VERSION 5.7 ;
BUSBITCHARS "[]" ;
DIVIDERCHAR "/" ;

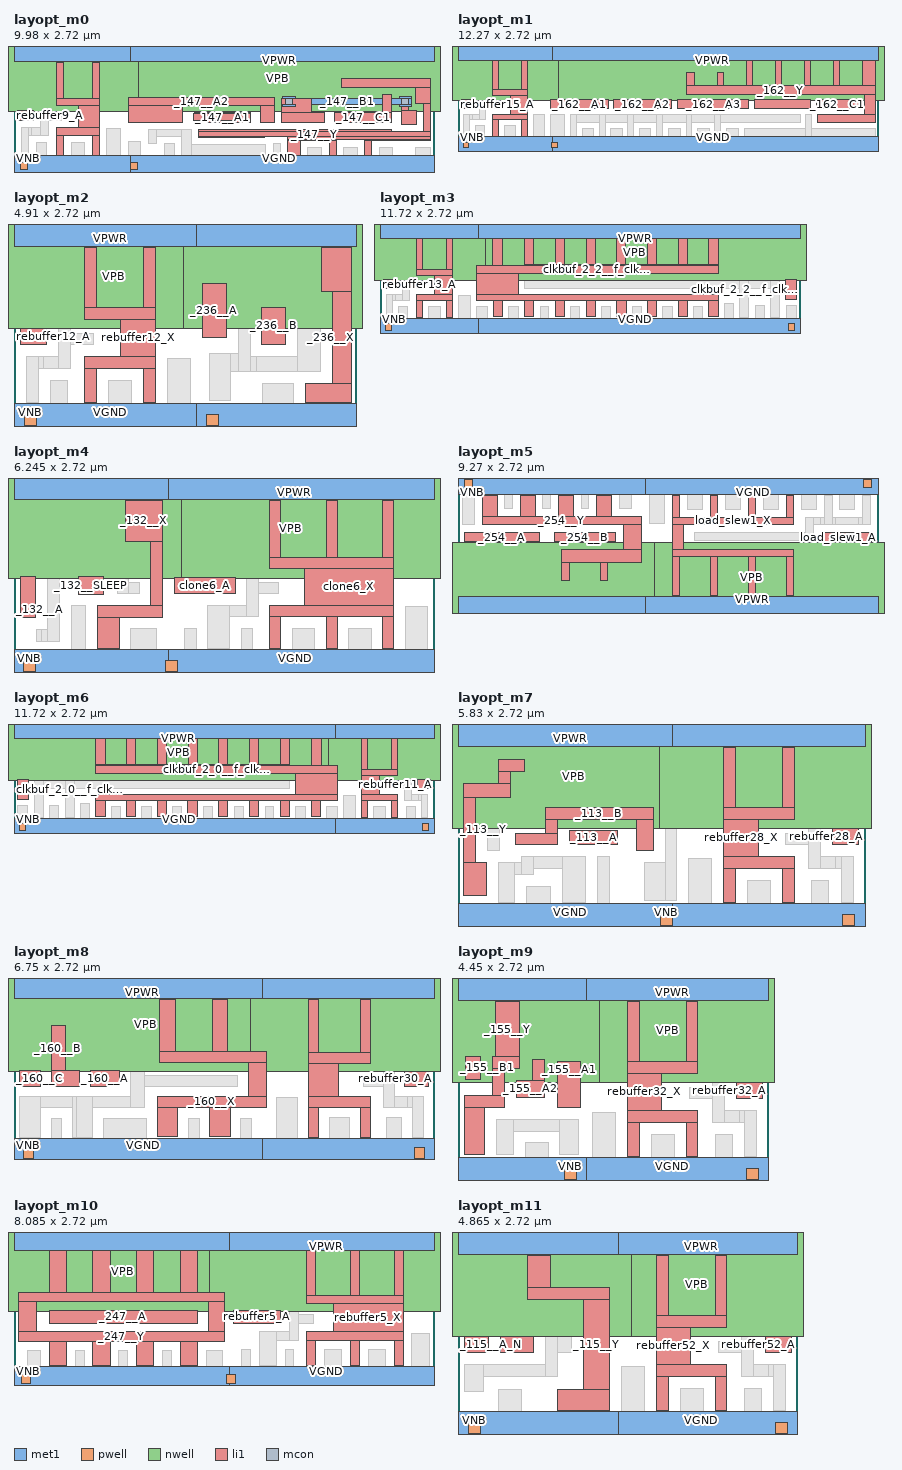
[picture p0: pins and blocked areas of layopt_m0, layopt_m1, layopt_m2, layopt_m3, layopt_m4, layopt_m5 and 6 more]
MACRO layopt_m0
  CLASS BLOCK ;
  FOREIGN layopt_m0 0 0 ;
  ORIGIN 0 0 ;
  SIZE 9.980 BY 2.720 ;
  SYMMETRY X Y ;
  PIN VGND
    DIRECTION INOUT ;
    USE GROUND ;
    SHAPE ABUTMENT ;
    PORT
      LAYER met1 ;
        RECT 0.000 -0.240 2.760 0.240 ;
      LAYER met1 ;
        RECT 2.620 -0.240 9.980 0.240 ;
    END
  END VGND
  PIN VNB
    DIRECTION INOUT ;
    USE GROUND ;
    SHAPE ABUTMENT ;
    PORT
      LAYER pwell ;
        RECT 0.150 -0.085 0.320 0.085 ;
      LAYER pwell ;
        RECT 2.770 -0.085 2.940 0.085 ;
    END
  END VNB
  PIN VPB
    DIRECTION INOUT ;
    USE POWER ;
    SHAPE ABUTMENT ;
    PORT
      LAYER nwell ;
        RECT -0.190 1.305 2.950 2.910 ;
      LAYER nwell ;
        RECT 2.430 1.305 10.170 2.910 ;
    END
  END VPB
  PIN VPWR
    DIRECTION INOUT ;
    USE POWER ;
    SHAPE ABUTMENT ;
    PORT
      LAYER met1 ;
        RECT 0.000 2.480 2.760 2.960 ;
      LAYER met1 ;
        RECT 2.620 2.480 9.980 2.960 ;
    END
  END VPWR
  PIN _147__A1
    DIRECTION INPUT ;
    USE SIGNAL ;
    PORT
      LAYER li1 ;
        RECT 4.275 1.075 5.625 1.245 ;
      LAYER li1 ;
        RECT 4.280 1.035 5.625 1.075 ;
      LAYER li1 ;
        RECT 4.280 1.245 5.625 1.275 ;
    END
  END _147__A1
  PIN _147__A2
    DIRECTION INPUT ;
    USE SIGNAL ;
    PORT
      LAYER li1 ;
        RECT 2.720 1.035 4.005 1.445 ;
      LAYER li1 ;
        RECT 2.720 1.445 6.195 1.625 ;
      LAYER li1 ;
        RECT 5.865 1.035 6.195 1.445 ;
    END
  END _147__A2
  PIN _147__B1
    DIRECTION INPUT ;
    USE SIGNAL ;
    PORT
      LAYER li1 ;
        RECT 6.365 1.035 7.375 1.275 ;
      LAYER li1 ;
        RECT 6.365 1.275 7.080 1.615 ;
      LAYER mcon ;
        RECT 6.450 1.445 6.620 1.615 ;
      LAYER li1 ;
        RECT 9.210 0.995 9.555 1.325 ;
      LAYER li1 ;
        RECT 9.210 1.325 9.380 1.615 ;
      LAYER mcon ;
        RECT 9.210 1.445 9.380 1.615 ;
      LAYER met1 ;
        RECT 6.390 1.415 6.680 1.460 ;
      LAYER met1 ;
        RECT 6.390 1.460 9.440 1.600 ;
      LAYER met1 ;
        RECT 6.390 1.600 6.680 1.645 ;
      LAYER met1 ;
        RECT 9.150 1.415 9.440 1.460 ;
      LAYER met1 ;
        RECT 9.150 1.600 9.440 1.645 ;
    END
  END _147__B1
  PIN _147__C1
    DIRECTION INPUT ;
    USE SIGNAL ;
    PORT
      LAYER li1 ;
        RECT 7.620 1.035 8.970 1.275 ;
      LAYER li1 ;
        RECT 8.750 1.275 8.970 1.695 ;
    END
  END _147__C1
  PIN _147__Y
    DIRECTION OUTPUT ;
    USE SIGNAL ;
    PORT
      LAYER li1 ;
        RECT 4.395 0.675 5.950 0.695 ;
      LAYER li1 ;
        RECT 4.395 0.695 9.895 0.825 ;
      LAYER li1 ;
        RECT 4.395 0.825 8.975 0.865 ;
      LAYER li1 ;
        RECT 6.495 0.255 6.815 0.615 ;
      LAYER li1 ;
        RECT 6.495 0.615 7.665 0.625 ;
      LAYER li1 ;
        RECT 6.495 0.625 9.895 0.695 ;
      LAYER li1 ;
        RECT 7.495 0.255 7.665 0.615 ;
      LAYER li1 ;
        RECT 7.790 1.865 9.895 2.085 ;
      LAYER li1 ;
        RECT 8.335 0.255 8.505 0.615 ;
      LAYER li1 ;
        RECT 8.335 0.615 9.895 0.625 ;
      LAYER li1 ;
        RECT 9.550 1.495 9.895 1.865 ;
      LAYER li1 ;
        RECT 9.725 0.825 9.895 1.495 ;
    END
  END _147__Y
  PIN rebuffer9_A
    DIRECTION INPUT ;
    USE SIGNAL ;
    PORT
      LAYER li1 ;
        RECT 0.090 1.075 0.470 1.315 ;
    END
  END rebuffer9_A
  PIN rebuffer9_X
    DIRECTION OUTPUT ;
    USE SIGNAL ;
    PORT
      LAYER li1 ;
        RECT 1.015 0.255 1.185 0.735 ;
      LAYER li1 ;
        RECT 1.015 0.735 2.025 0.905 ;
      LAYER li1 ;
        RECT 1.015 1.445 2.025 1.615 ;
      LAYER li1 ;
        RECT 1.015 1.615 1.185 2.465 ;
      LAYER li1 ;
        RECT 1.530 0.905 2.025 1.445 ;
      LAYER li1 ;
        RECT 1.855 0.255 2.025 0.735 ;
      LAYER li1 ;
        RECT 1.855 1.615 2.025 2.465 ;
    END
  END rebuffer9_X
  OBS
    LAYER li1 ;
      RECT 2.620 -0.085 2.715 0.085 ;
      RECT 2.715 -0.085 3.015 0.585 ;
      RECT 3.015 -0.085 3.570 0.085 ;
      RECT 3.570 -0.085 3.805 0.525 ;
      RECT 3.805 -0.085 6.155 0.085 ;
      RECT 6.155 -0.085 6.325 0.525 ;
      RECT 6.325 -0.085 6.985 0.085 ;
      RECT 6.985 -0.085 7.315 0.445 ;
      RECT 7.315 -0.085 7.835 0.085 ;
      RECT 7.835 -0.085 8.165 0.445 ;
      RECT 8.165 -0.085 8.675 0.085 ;
      RECT 8.675 -0.085 9.005 0.445 ;
      RECT 9.005 -0.085 9.535 0.085 ;
      RECT 9.535 -0.085 9.890 0.445 ;
      RECT 9.890 -0.085 9.980 0.085 ;
      RECT 2.620 2.635 3.135 2.805 ;
      RECT 3.135 2.255 3.465 2.805 ;
      RECT 3.465 2.635 3.975 2.805 ;
      RECT 3.975 2.275 4.305 2.805 ;
      RECT 4.305 2.635 4.815 2.805 ;
      RECT 4.815 2.275 5.145 2.805 ;
      RECT 5.145 2.635 5.655 2.805 ;
      RECT 5.655 2.275 5.985 2.805 ;
      RECT 5.985 2.635 9.980 2.805 ;
      RECT 6.495 1.785 7.250 2.085 ;
      RECT 7.250 1.445 7.530 2.085 ;
      RECT 7.530 1.445 8.580 1.695 ;
      RECT 2.715 1.795 2.965 2.465 ;
      RECT 2.965 1.795 3.635 2.085 ;
      RECT 3.635 1.795 3.805 2.465 ;
      RECT 3.805 1.795 4.475 2.105 ;
      RECT 4.475 1.795 4.645 2.465 ;
      RECT 4.645 1.795 5.315 2.105 ;
      RECT 5.315 1.795 5.485 2.465 ;
      RECT 5.485 1.795 6.155 2.105 ;
      RECT 6.155 1.795 6.325 2.465 ;
      RECT 6.325 2.255 9.890 2.465 ;
      RECT 3.185 0.530 3.395 0.865 ;
      RECT 3.395 0.695 3.975 0.865 ;
      RECT 3.975 0.255 4.225 0.865 ;
      RECT 4.225 0.255 5.985 0.505 ;
      RECT 0.095 1.485 0.175 2.465 ;
      RECT 0.175 0.255 0.345 0.905 ;
      RECT 0.175 1.485 0.345 2.465 ;
      RECT 0.345 0.735 0.425 0.905 ;
      RECT 0.345 1.485 0.425 2.465 ;
      RECT 0.425 0.735 0.640 0.905 ;
      RECT 0.425 1.485 0.640 1.655 ;
      RECT 0.640 0.735 0.810 1.655 ;
      RECT 0.810 1.075 1.140 1.245 ;
      RECT 0.000 2.635 0.595 2.805 ;
      RECT 0.595 1.835 0.835 2.805 ;
      RECT 0.835 2.635 1.355 2.805 ;
      RECT 1.355 1.835 1.685 2.805 ;
      RECT 1.685 2.635 2.195 2.805 ;
      RECT 2.195 1.485 2.525 2.805 ;
      RECT 2.525 2.635 2.760 2.805 ;
      RECT 0.000 -0.085 0.525 0.085 ;
      RECT 0.525 -0.085 0.765 0.565 ;
      RECT 0.765 -0.085 1.355 0.085 ;
      RECT 1.355 -0.085 1.685 0.565 ;
      RECT 1.685 -0.085 2.195 0.085 ;
      RECT 2.195 -0.085 2.525 0.885 ;
      RECT 2.525 -0.085 2.760 0.085 ;
  END
END layopt_m0

MACRO layopt_m1
  CLASS BLOCK ;
  FOREIGN layopt_m1 0 0 ;
  ORIGIN 0 0 ;
  SIZE 12.270 BY 2.720 ;
  SYMMETRY X Y ;
  PIN VGND
    DIRECTION INOUT ;
    USE GROUND ;
    SHAPE ABUTMENT ;
    PORT
      LAYER met1 ;
        RECT 0.000 -0.240 2.760 0.240 ;
      LAYER met1 ;
        RECT 2.610 -0.240 12.270 0.240 ;
    END
  END VGND
  PIN VNB
    DIRECTION INOUT ;
    USE GROUND ;
    SHAPE ABUTMENT ;
    PORT
      LAYER pwell ;
        RECT 0.150 -0.085 0.320 0.085 ;
      LAYER pwell ;
        RECT 2.735 -0.085 2.905 0.085 ;
    END
  END VNB
  PIN VPB
    DIRECTION INOUT ;
    USE POWER ;
    SHAPE ABUTMENT ;
    PORT
      LAYER nwell ;
        RECT -0.190 1.305 2.950 2.910 ;
      LAYER nwell ;
        RECT 2.420 1.305 12.460 2.910 ;
    END
  END VPB
  PIN VPWR
    DIRECTION INOUT ;
    USE POWER ;
    SHAPE ABUTMENT ;
    PORT
      LAYER met1 ;
        RECT 0.000 2.480 2.760 2.960 ;
      LAYER met1 ;
        RECT 2.610 2.480 12.270 2.960 ;
    END
  END VPWR
  PIN _162__A1
    DIRECTION INPUT ;
    USE SIGNAL ;
    PORT
      LAYER li1 ;
        RECT 2.695 1.055 4.385 1.315 ;
    END
  END _162__A1
  PIN _162__A2
    DIRECTION INPUT ;
    USE SIGNAL ;
    PORT
      LAYER li1 ;
        RECT 4.555 1.055 6.225 1.315 ;
    END
  END _162__A2
  PIN _162__A3
    DIRECTION INPUT ;
    USE SIGNAL ;
    PORT
      LAYER li1 ;
        RECT 6.415 1.055 8.495 1.315 ;
    END
  END _162__A3
  PIN _162__B1
    DIRECTION INPUT ;
    USE SIGNAL ;
    PORT
      LAYER li1 ;
        RECT 8.665 1.055 10.305 1.315 ;
    END
  END _162__B1
  PIN _162__C1
    DIRECTION INPUT ;
    USE SIGNAL ;
    PORT
      LAYER li1 ;
        RECT 10.475 1.055 11.700 1.315 ;
    END
  END _162__C1
  PIN _162__Y
    DIRECTION OUTPUT ;
    USE SIGNAL ;
    PORT
      LAYER li1 ;
        RECT 6.665 1.485 12.185 1.725 ;
      LAYER li1 ;
        RECT 6.665 1.725 6.915 2.115 ;
      LAYER li1 ;
        RECT 7.585 1.725 7.755 2.115 ;
      LAYER li1 ;
        RECT 8.425 1.725 8.615 2.465 ;
      LAYER li1 ;
        RECT 9.285 1.725 9.455 2.465 ;
      LAYER li1 ;
        RECT 10.125 1.725 10.295 2.465 ;
      LAYER li1 ;
        RECT 10.505 0.655 12.185 0.885 ;
      LAYER li1 ;
        RECT 10.965 1.725 11.135 2.465 ;
      LAYER li1 ;
        RECT 11.805 1.725 12.185 2.465 ;
      LAYER li1 ;
        RECT 11.870 0.885 12.185 1.485 ;
    END
  END _162__Y
  PIN rebuffer15_A
    DIRECTION INPUT ;
    USE SIGNAL ;
    PORT
      LAYER li1 ;
        RECT 0.090 1.075 0.470 1.315 ;
    END
  END rebuffer15_A
  PIN rebuffer15_X
    DIRECTION OUTPUT ;
    USE SIGNAL ;
    PORT
      LAYER li1 ;
        RECT 1.015 0.255 1.185 0.735 ;
      LAYER li1 ;
        RECT 1.015 0.735 2.025 0.905 ;
      LAYER li1 ;
        RECT 1.015 1.445 2.025 1.615 ;
      LAYER li1 ;
        RECT 1.015 1.615 1.185 2.465 ;
      LAYER li1 ;
        RECT 1.530 0.905 2.025 1.445 ;
      LAYER li1 ;
        RECT 1.855 0.255 2.025 0.735 ;
      LAYER li1 ;
        RECT 1.855 1.615 2.025 2.465 ;
    END
  END rebuffer15_X
  OBS
    LAYER li1 ;
      RECT 2.610 -0.085 2.695 0.085 ;
      RECT 2.695 -0.085 3.115 0.885 ;
      RECT 3.115 -0.085 3.625 0.085 ;
      RECT 3.625 -0.085 3.955 0.485 ;
      RECT 3.955 -0.085 4.465 0.085 ;
      RECT 4.465 -0.085 4.795 0.485 ;
      RECT 4.795 -0.085 5.305 0.085 ;
      RECT 5.305 -0.085 5.635 0.485 ;
      RECT 5.635 -0.085 6.145 0.085 ;
      RECT 6.145 -0.085 6.495 0.485 ;
      RECT 6.495 -0.085 7.005 0.085 ;
      RECT 7.005 -0.085 7.335 0.485 ;
      RECT 7.335 -0.085 7.845 0.085 ;
      RECT 7.845 -0.085 8.195 0.485 ;
      RECT 8.195 -0.085 12.270 0.085 ;
      RECT 8.365 0.255 10.165 0.485 ;
      RECT 10.165 0.255 10.335 0.885 ;
      RECT 10.335 0.255 12.185 0.485 ;
      RECT 2.695 1.485 3.015 2.465 ;
      RECT 3.015 1.485 3.705 1.725 ;
      RECT 3.705 1.485 3.875 2.465 ;
      RECT 3.875 1.485 4.545 1.725 ;
      RECT 4.545 1.485 4.715 2.465 ;
      RECT 4.715 1.485 5.385 1.725 ;
      RECT 5.385 1.485 5.555 2.115 ;
      RECT 5.555 1.485 6.225 1.725 ;
      RECT 6.225 1.485 6.475 2.115 ;
      RECT 3.285 0.255 3.455 0.885 ;
      RECT 3.455 0.655 4.125 0.885 ;
      RECT 4.125 0.255 4.295 0.885 ;
      RECT 4.295 0.655 4.965 0.885 ;
      RECT 4.965 0.255 5.135 0.885 ;
      RECT 5.135 0.655 5.805 0.885 ;
      RECT 5.805 0.255 5.975 0.885 ;
      RECT 5.975 0.655 6.665 0.885 ;
      RECT 6.665 0.255 6.835 0.885 ;
      RECT 6.835 0.655 7.505 0.885 ;
      RECT 7.505 0.255 7.675 0.885 ;
      RECT 7.675 0.655 9.995 0.885 ;
      RECT 2.610 2.635 3.205 2.805 ;
      RECT 3.205 1.895 3.535 2.805 ;
      RECT 3.535 2.635 4.045 2.805 ;
      RECT 4.045 1.895 4.375 2.805 ;
      RECT 4.375 2.635 8.785 2.805 ;
      RECT 8.785 1.895 9.115 2.805 ;
      RECT 9.115 2.635 9.625 2.805 ;
      RECT 9.625 1.895 9.955 2.805 ;
      RECT 9.955 2.635 10.465 2.805 ;
      RECT 10.465 1.895 10.795 2.805 ;
      RECT 10.795 2.635 11.305 2.805 ;
      RECT 11.305 1.895 11.635 2.805 ;
      RECT 11.635 2.635 12.270 2.805 ;
      RECT 4.885 1.895 5.215 2.465 ;
      RECT 5.215 2.295 5.725 2.465 ;
      RECT 5.725 1.895 6.055 2.465 ;
      RECT 6.055 2.295 7.085 2.465 ;
      RECT 7.085 1.895 7.415 2.465 ;
      RECT 7.415 2.295 7.925 2.465 ;
      RECT 7.925 1.895 8.255 2.465 ;
      RECT 0.095 1.485 0.175 2.465 ;
      RECT 0.175 0.255 0.345 0.905 ;
      RECT 0.175 1.485 0.345 2.465 ;
      RECT 0.345 0.735 0.425 0.905 ;
      RECT 0.345 1.485 0.425 2.465 ;
      RECT 0.425 0.735 0.640 0.905 ;
      RECT 0.425 1.485 0.640 1.655 ;
      RECT 0.640 0.735 0.810 1.655 ;
      RECT 0.810 1.075 1.140 1.245 ;
      RECT 0.000 2.635 0.595 2.805 ;
      RECT 0.595 1.835 0.835 2.805 ;
      RECT 0.835 2.635 1.355 2.805 ;
      RECT 1.355 1.835 1.685 2.805 ;
      RECT 1.685 2.635 2.195 2.805 ;
      RECT 2.195 1.485 2.525 2.805 ;
      RECT 2.525 2.635 2.760 2.805 ;
      RECT 0.000 -0.085 0.525 0.085 ;
      RECT 0.525 -0.085 0.765 0.565 ;
      RECT 0.765 -0.085 1.355 0.085 ;
      RECT 1.355 -0.085 1.685 0.565 ;
      RECT 1.685 -0.085 2.195 0.085 ;
      RECT 2.195 -0.085 2.525 0.885 ;
      RECT 2.525 -0.085 2.760 0.085 ;
  END
END layopt_m1

MACRO layopt_m2
  CLASS BLOCK ;
  FOREIGN layopt_m2 0 0 ;
  ORIGIN 0 0 ;
  SIZE 4.910 BY 2.720 ;
  SYMMETRY X Y ;
  PIN VGND
    DIRECTION INOUT ;
    USE GROUND ;
    SHAPE ABUTMENT ;
    PORT
      LAYER met1 ;
        RECT 0.000 -0.240 2.760 0.240 ;
      LAYER met1 ;
        RECT 2.610 -0.240 4.910 0.240 ;
    END
  END VGND
  PIN VNB
    DIRECTION INOUT ;
    USE GROUND ;
    SHAPE ABUTMENT ;
    PORT
      LAYER pwell ;
        RECT 0.150 -0.085 0.320 0.085 ;
      LAYER pwell ;
        RECT 2.755 -0.085 2.925 0.085 ;
    END
  END VNB
  PIN VPB
    DIRECTION INOUT ;
    USE POWER ;
    SHAPE ABUTMENT ;
    PORT
      LAYER nwell ;
        RECT -0.190 1.305 2.950 2.910 ;
      LAYER nwell ;
        RECT 2.420 1.305 5.100 2.910 ;
    END
  END VPB
  PIN VPWR
    DIRECTION INOUT ;
    USE POWER ;
    SHAPE ABUTMENT ;
    PORT
      LAYER met1 ;
        RECT 0.000 2.480 2.760 2.960 ;
      LAYER met1 ;
        RECT 2.610 2.480 4.910 2.960 ;
    END
  END VPWR
  PIN _236__A
    DIRECTION INPUT ;
    USE SIGNAL ;
    PORT
      LAYER li1 ;
        RECT 2.695 1.185 3.040 1.955 ;
    END
  END _236__A
  PIN _236__B
    DIRECTION INPUT ;
    USE SIGNAL ;
    PORT
      LAYER li1 ;
        RECT 3.550 1.080 3.880 1.615 ;
    END
  END _236__B
  PIN _236__X
    DIRECTION OUTPUT ;
    USE SIGNAL ;
    PORT
      LAYER li1 ;
        RECT 4.170 0.255 4.825 0.525 ;
      LAYER li1 ;
        RECT 4.400 1.835 4.825 2.465 ;
      LAYER li1 ;
        RECT 4.560 0.525 4.825 1.835 ;
    END
  END _236__X
  PIN rebuffer12_A
    DIRECTION INPUT ;
    USE SIGNAL ;
    PORT
      LAYER li1 ;
        RECT 0.090 1.075 0.470 1.315 ;
    END
  END rebuffer12_A
  PIN rebuffer12_X
    DIRECTION OUTPUT ;
    USE SIGNAL ;
    PORT
      LAYER li1 ;
        RECT 1.015 0.255 1.185 0.735 ;
      LAYER li1 ;
        RECT 1.015 0.735 2.025 0.905 ;
      LAYER li1 ;
        RECT 1.015 1.445 2.025 1.615 ;
      LAYER li1 ;
        RECT 1.015 1.615 1.185 2.465 ;
      LAYER li1 ;
        RECT 1.530 0.905 2.025 1.445 ;
      LAYER li1 ;
        RECT 1.855 0.255 2.025 0.735 ;
      LAYER li1 ;
        RECT 1.855 1.615 2.025 2.465 ;
    END
  END rebuffer12_X
  OBS
    LAYER li1 ;
      RECT 2.610 -0.085 3.560 0.085 ;
      RECT 3.560 -0.085 4.000 0.525 ;
      RECT 4.000 -0.085 4.910 0.085 ;
      RECT 2.610 2.635 2.770 2.805 ;
      RECT 2.770 2.175 3.040 2.805 ;
      RECT 3.040 2.635 3.720 2.805 ;
      RECT 3.720 1.835 4.230 2.805 ;
      RECT 4.230 2.635 4.910 2.805 ;
      RECT 2.795 0.280 3.100 0.950 ;
      RECT 3.100 0.695 3.210 0.950 ;
      RECT 3.210 0.695 3.380 2.465 ;
      RECT 3.380 0.695 3.475 0.910 ;
      RECT 3.380 2.135 3.475 2.465 ;
      RECT 3.475 0.695 4.060 0.910 ;
      RECT 4.060 0.695 4.390 1.435 ;
      RECT 0.095 1.485 0.175 2.465 ;
      RECT 0.175 0.255 0.345 0.905 ;
      RECT 0.175 1.485 0.345 2.465 ;
      RECT 0.345 0.735 0.425 0.905 ;
      RECT 0.345 1.485 0.425 2.465 ;
      RECT 0.425 0.735 0.640 0.905 ;
      RECT 0.425 1.485 0.640 1.655 ;
      RECT 0.640 0.735 0.810 1.655 ;
      RECT 0.810 1.075 1.140 1.245 ;
      RECT 0.000 2.635 0.595 2.805 ;
      RECT 0.595 1.835 0.835 2.805 ;
      RECT 0.835 2.635 1.355 2.805 ;
      RECT 1.355 1.835 1.685 2.805 ;
      RECT 1.685 2.635 2.195 2.805 ;
      RECT 2.195 1.485 2.525 2.805 ;
      RECT 2.525 2.635 2.760 2.805 ;
      RECT 0.000 -0.085 0.525 0.085 ;
      RECT 0.525 -0.085 0.765 0.565 ;
      RECT 0.765 -0.085 1.355 0.085 ;
      RECT 1.355 -0.085 1.685 0.565 ;
      RECT 1.685 -0.085 2.195 0.085 ;
      RECT 2.195 -0.085 2.525 0.885 ;
      RECT 2.525 -0.085 2.760 0.085 ;
  END
END layopt_m2

MACRO layopt_m3
  CLASS BLOCK ;
  FOREIGN layopt_m3 0 0 ;
  ORIGIN 0 0 ;
  SIZE 11.720 BY 2.720 ;
  SYMMETRY X Y ;
  PIN VGND
    DIRECTION INOUT ;
    USE GROUND ;
    SHAPE ABUTMENT ;
    PORT
      LAYER met1 ;
        RECT 0.000 -0.240 2.760 0.240 ;
      LAYER met1 ;
        RECT 2.520 -0.240 11.720 0.240 ;
    END
  END VGND
  PIN VNB
    DIRECTION INOUT ;
    USE GROUND ;
    SHAPE ABUTMENT ;
    PORT
      LAYER pwell ;
        RECT 0.150 -0.085 0.320 0.085 ;
      LAYER pwell ;
        RECT 11.405 -0.085 11.575 0.085 ;
    END
  END VNB
  PIN VPB
    DIRECTION INOUT ;
    USE POWER ;
    SHAPE ABUTMENT ;
    PORT
      LAYER nwell ;
        RECT -0.190 1.305 2.950 2.910 ;
      LAYER nwell ;
        RECT 2.330 1.305 11.910 2.910 ;
    END
  END VPB
  PIN VPWR
    DIRECTION INOUT ;
    USE POWER ;
    SHAPE ABUTMENT ;
    PORT
      LAYER met1 ;
        RECT 0.000 2.480 2.760 2.960 ;
      LAYER met1 ;
        RECT 2.520 2.480 11.720 2.960 ;
    END
  END VPWR
  PIN clkbuf_2_2__f_clk_A
    DIRECTION INPUT ;
    USE SIGNAL ;
    PORT
      LAYER li1 ;
        RECT 11.320 0.765 11.635 1.325 ;
    END
  END clkbuf_2_2__f_clk_A
  PIN clkbuf_2_2__f_clk_X
    DIRECTION OUTPUT ;
    USE SIGNAL ;
    PORT
      LAYER li1 ;
        RECT 9.180 0.280 9.440 0.735 ;
      LAYER li1 ;
        RECT 2.695 0.735 9.440 0.905 ;
      LAYER li1 ;
        RECT 2.695 1.495 9.440 1.720 ;
      LAYER li1 ;
        RECT 4.035 1.720 9.440 1.735 ;
      LAYER li1 ;
        RECT 9.180 1.735 9.440 2.460 ;
      LAYER li1 ;
        RECT 8.320 0.280 8.580 0.735 ;
      LAYER li1 ;
        RECT 8.320 1.735 8.580 2.460 ;
      LAYER li1 ;
        RECT 7.460 0.280 7.720 0.735 ;
      LAYER li1 ;
        RECT 7.460 1.735 7.720 2.460 ;
      LAYER li1 ;
        RECT 6.600 0.280 6.875 0.735 ;
      LAYER li1 ;
        RECT 6.600 1.735 6.860 2.460 ;
      LAYER li1 ;
        RECT 5.755 0.280 6.015 0.735 ;
      LAYER li1 ;
        RECT 5.755 1.735 6.015 2.460 ;
      LAYER li1 ;
        RECT 4.895 0.280 5.155 0.735 ;
      LAYER li1 ;
        RECT 4.895 1.735 5.155 2.460 ;
      LAYER li1 ;
        RECT 4.035 0.280 4.295 0.735 ;
      LAYER li1 ;
        RECT 4.035 1.735 4.295 2.460 ;
      LAYER li1 ;
        RECT 2.695 0.905 3.860 1.495 ;
      LAYER li1 ;
        RECT 3.165 0.280 3.425 0.735 ;
      LAYER li1 ;
        RECT 3.135 1.720 3.425 2.460 ;
    END
  END clkbuf_2_2__f_clk_X
  PIN rebuffer13_A
    DIRECTION INPUT ;
    USE SIGNAL ;
    PORT
      LAYER li1 ;
        RECT 0.090 1.075 0.470 1.315 ;
    END
  END rebuffer13_A
  PIN rebuffer13_X
    DIRECTION OUTPUT ;
    USE SIGNAL ;
    PORT
      LAYER li1 ;
        RECT 1.015 0.255 1.185 0.735 ;
      LAYER li1 ;
        RECT 1.015 0.735 2.025 0.905 ;
      LAYER li1 ;
        RECT 1.015 1.445 2.025 1.615 ;
      LAYER li1 ;
        RECT 1.015 1.615 1.185 2.465 ;
      LAYER li1 ;
        RECT 1.530 0.905 2.025 1.445 ;
      LAYER li1 ;
        RECT 1.855 0.255 2.025 0.735 ;
      LAYER li1 ;
        RECT 1.855 1.615 2.025 2.465 ;
    END
  END rebuffer13_X
  OBS
    LAYER li1 ;
      RECT 11.625 2.635 11.720 2.805 ;
      RECT 11.330 1.825 11.625 2.805 ;
      RECT 10.730 2.635 11.330 2.805 ;
      RECT 10.470 1.825 10.730 2.805 ;
      RECT 9.870 2.635 10.470 2.805 ;
      RECT 9.610 1.835 9.870 2.805 ;
      RECT 9.010 2.630 9.610 2.805 ;
      RECT 8.750 1.905 9.010 2.805 ;
      RECT 8.150 2.630 8.750 2.805 ;
      RECT 7.890 1.905 8.150 2.805 ;
      RECT 7.290 2.630 7.890 2.805 ;
      RECT 7.030 1.905 7.290 2.805 ;
      RECT 6.430 2.630 7.030 2.805 ;
      RECT 6.185 1.905 6.430 2.805 ;
      RECT 5.570 2.630 6.185 2.805 ;
      RECT 5.325 1.905 5.570 2.805 ;
      RECT 4.710 2.630 5.325 2.805 ;
      RECT 4.465 1.905 4.710 2.805 ;
      RECT 3.850 2.630 4.465 2.805 ;
      RECT 3.595 1.905 3.850 2.805 ;
      RECT 2.965 2.635 3.595 2.805 ;
      RECT 2.695 1.890 2.965 2.805 ;
      RECT 2.520 2.635 2.695 2.805 ;
      RECT 11.635 -0.085 11.720 0.085 ;
      RECT 11.330 -0.085 11.635 0.595 ;
      RECT 10.730 -0.085 11.330 0.085 ;
      RECT 10.470 -0.085 10.730 0.610 ;
      RECT 9.870 -0.085 10.470 0.085 ;
      RECT 9.610 -0.085 9.870 0.645 ;
      RECT 9.010 -0.085 9.610 0.085 ;
      RECT 8.750 -0.085 9.010 0.565 ;
      RECT 8.150 -0.085 8.750 0.085 ;
      RECT 7.890 -0.085 8.150 0.565 ;
      RECT 7.290 -0.085 7.890 0.085 ;
      RECT 7.045 -0.085 7.290 0.565 ;
      RECT 6.430 -0.085 7.045 0.085 ;
      RECT 6.185 -0.085 6.430 0.565 ;
      RECT 5.575 -0.085 6.185 0.085 ;
      RECT 5.325 -0.085 5.575 0.565 ;
      RECT 4.715 -0.085 5.325 0.085 ;
      RECT 4.465 -0.085 4.715 0.565 ;
      RECT 3.855 -0.085 4.465 0.085 ;
      RECT 3.595 -0.085 3.855 0.565 ;
      RECT 2.995 -0.085 3.595 0.085 ;
      RECT 2.695 -0.085 2.995 0.565 ;
      RECT 2.520 -0.085 2.695 0.085 ;
      RECT 10.905 0.265 11.150 2.465 ;
      RECT 10.900 0.265 10.905 1.325 ;
      RECT 10.290 1.075 10.900 1.325 ;
      RECT 10.040 0.265 10.290 2.460 ;
      RECT 4.030 1.075 10.040 1.325 ;
      RECT 0.095 1.485 0.175 2.465 ;
      RECT 0.175 0.255 0.345 0.905 ;
      RECT 0.175 1.485 0.345 2.465 ;
      RECT 0.345 0.735 0.425 0.905 ;
      RECT 0.345 1.485 0.425 2.465 ;
      RECT 0.425 0.735 0.640 0.905 ;
      RECT 0.425 1.485 0.640 1.655 ;
      RECT 0.640 0.735 0.810 1.655 ;
      RECT 0.810 1.075 1.140 1.245 ;
      RECT 0.000 2.635 0.595 2.805 ;
      RECT 0.595 1.835 0.835 2.805 ;
      RECT 0.835 2.635 1.355 2.805 ;
      RECT 1.355 1.835 1.685 2.805 ;
      RECT 1.685 2.635 2.195 2.805 ;
      RECT 2.195 1.485 2.525 2.805 ;
      RECT 2.525 2.635 2.760 2.805 ;
      RECT 0.000 -0.085 0.525 0.085 ;
      RECT 0.525 -0.085 0.765 0.565 ;
      RECT 0.765 -0.085 1.355 0.085 ;
      RECT 1.355 -0.085 1.685 0.565 ;
      RECT 1.685 -0.085 2.195 0.085 ;
      RECT 2.195 -0.085 2.525 0.885 ;
      RECT 2.525 -0.085 2.760 0.085 ;
  END
END layopt_m3

MACRO layopt_m4
  CLASS BLOCK ;
  FOREIGN layopt_m4 0 0 ;
  ORIGIN 0 0 ;
  SIZE 6.245 BY 2.720 ;
  SYMMETRY X Y ;
  PIN VGND
    DIRECTION INOUT ;
    USE GROUND ;
    SHAPE ABUTMENT ;
    PORT
      LAYER met1 ;
        RECT 0.000 -0.240 2.300 0.240 ;
      LAYER met1 ;
        RECT 2.105 -0.240 6.245 0.240 ;
    END
  END VGND
  PIN VNB
    DIRECTION INOUT ;
    USE GROUND ;
    SHAPE ABUTMENT ;
    PORT
      LAYER pwell ;
        RECT 0.145 -0.085 0.315 0.085 ;
      LAYER pwell ;
        RECT 2.255 -0.085 2.425 0.085 ;
    END
  END VNB
  PIN VPB
    DIRECTION INOUT ;
    USE POWER ;
    SHAPE ABUTMENT ;
    PORT
      LAYER nwell ;
        RECT -0.190 1.305 2.490 2.910 ;
      LAYER nwell ;
        RECT 1.915 1.305 6.435 2.910 ;
    END
  END VPB
  PIN VPWR
    DIRECTION INOUT ;
    USE POWER ;
    SHAPE ABUTMENT ;
    PORT
      LAYER met1 ;
        RECT 0.000 2.480 2.300 2.960 ;
      LAYER met1 ;
        RECT 2.105 2.480 6.245 2.960 ;
    END
  END VPWR
  PIN _132__A
    DIRECTION INPUT ;
    USE SIGNAL ;
    PORT
      LAYER li1 ;
        RECT 0.100 0.725 0.325 1.325 ;
    END
  END _132__A
  PIN _132__SLEEP
    DIRECTION INPUT ;
    USE SIGNAL ;
    PORT
      LAYER li1 ;
        RECT 0.960 1.065 1.325 1.325 ;
    END
  END _132__SLEEP
  PIN _132__X
    DIRECTION OUTPUT ;
    USE SIGNAL ;
    PORT
      LAYER li1 ;
        RECT 1.235 0.255 1.565 0.725 ;
      LAYER li1 ;
        RECT 1.235 0.725 2.215 0.895 ;
      LAYER li1 ;
        RECT 1.655 1.850 2.215 2.465 ;
      LAYER li1 ;
        RECT 2.035 0.895 2.215 1.850 ;
    END
  END _132__X
  PIN clone6_A
    DIRECTION INPUT ;
    USE SIGNAL ;
    PORT
      LAYER li1 ;
        RECT 2.385 1.075 3.290 1.315 ;
    END
  END clone6_A
  PIN clone6_X
    DIRECTION OUTPUT ;
    USE SIGNAL ;
    PORT
      LAYER li1 ;
        RECT 3.800 0.255 3.970 0.735 ;
      LAYER li1 ;
        RECT 3.800 0.735 5.650 0.905 ;
      LAYER li1 ;
        RECT 3.800 1.445 5.650 1.615 ;
      LAYER li1 ;
        RECT 3.800 1.615 3.970 2.465 ;
      LAYER li1 ;
        RECT 4.315 0.905 5.650 1.445 ;
      LAYER li1 ;
        RECT 4.640 0.255 4.810 0.735 ;
      LAYER li1 ;
        RECT 4.640 1.615 4.810 2.465 ;
      LAYER li1 ;
        RECT 5.480 0.255 5.650 0.735 ;
      LAYER li1 ;
        RECT 5.480 1.615 5.650 2.465 ;
    END
  END clone6_X
  OBS
    LAYER li1 ;
      RECT 0.000 -0.085 0.855 0.085 ;
      RECT 0.855 -0.085 1.065 0.895 ;
      RECT 1.065 -0.085 1.735 0.085 ;
      RECT 1.735 -0.085 2.120 0.555 ;
      RECT 2.120 -0.085 2.300 0.085 ;
      RECT 0.000 2.635 0.875 2.805 ;
      RECT 0.875 1.855 1.205 2.805 ;
      RECT 1.205 2.635 2.300 2.805 ;
      RECT 0.330 0.370 0.415 0.545 ;
      RECT 0.415 0.370 0.495 0.545 ;
      RECT 0.415 1.510 0.495 1.905 ;
      RECT 0.495 0.370 0.675 1.905 ;
      RECT 0.675 1.510 1.535 1.680 ;
      RECT 1.535 1.075 1.705 1.680 ;
      RECT 1.705 1.075 1.865 1.245 ;
      RECT 2.880 0.255 3.210 0.905 ;
      RECT 2.880 1.485 3.210 2.465 ;
      RECT 3.210 0.735 3.460 0.905 ;
      RECT 3.210 1.485 3.460 1.655 ;
      RECT 3.460 0.735 3.630 1.655 ;
      RECT 3.630 1.075 3.930 1.245 ;
      RECT 2.105 -0.085 2.540 0.085 ;
      RECT 2.540 -0.085 2.710 0.565 ;
      RECT 2.710 -0.085 3.380 0.085 ;
      RECT 3.380 -0.085 3.550 0.565 ;
      RECT 3.550 -0.085 4.140 0.085 ;
      RECT 4.140 -0.085 4.470 0.565 ;
      RECT 4.470 -0.085 4.980 0.085 ;
      RECT 4.980 -0.085 5.310 0.565 ;
      RECT 5.310 -0.085 5.820 0.085 ;
      RECT 5.820 -0.085 6.150 0.885 ;
      RECT 6.150 -0.085 6.245 0.085 ;
      RECT 2.105 2.635 2.540 2.805 ;
      RECT 2.540 1.485 2.710 2.805 ;
      RECT 2.710 2.635 3.380 2.805 ;
      RECT 3.380 1.835 3.620 2.805 ;
      RECT 3.620 2.635 4.140 2.805 ;
      RECT 4.140 1.835 4.470 2.805 ;
      RECT 4.470 2.635 4.980 2.805 ;
      RECT 4.980 1.835 5.310 2.805 ;
      RECT 5.310 2.635 5.820 2.805 ;
      RECT 5.820 1.485 6.150 2.805 ;
      RECT 6.150 2.635 6.245 2.805 ;
  END
END layopt_m4

MACRO layopt_m5
  CLASS BLOCK ;
  FOREIGN layopt_m5 0 0 ;
  ORIGIN 0 0 ;
  SIZE 9.270 BY 2.720 ;
  SYMMETRY X Y ;
  PIN VGND
    DIRECTION INOUT ;
    USE GROUND ;
    SHAPE ABUTMENT ;
    PORT
      LAYER met1 ;
        RECT 0.000 2.480 4.140 2.960 ;
      LAYER met1 ;
        RECT 3.750 2.480 9.270 2.960 ;
    END
  END VGND
  PIN VNB
    DIRECTION INOUT ;
    USE GROUND ;
    SHAPE ABUTMENT ;
    PORT
      LAYER pwell ;
        RECT 0.150 2.635 0.320 2.805 ;
      LAYER pwell ;
        RECT 8.950 2.635 9.120 2.805 ;
    END
  END VNB
  PIN VPB
    DIRECTION INOUT ;
    USE POWER ;
    SHAPE ABUTMENT ;
    PORT
      LAYER nwell ;
        RECT -0.190 -0.190 4.330 1.415 ;
      LAYER nwell ;
        RECT 3.560 -0.190 9.460 1.415 ;
    END
  END VPB
  PIN VPWR
    DIRECTION INOUT ;
    USE POWER ;
    SHAPE ABUTMENT ;
    PORT
      LAYER met1 ;
        RECT 0.000 -0.240 4.140 0.240 ;
      LAYER met1 ;
        RECT 3.750 -0.240 9.270 0.240 ;
    END
  END VPWR
  PIN _254__A
    DIRECTION INPUT ;
    USE SIGNAL ;
    PORT
      LAYER li1 ;
        RECT 0.140 1.445 1.800 1.645 ;
    END
  END _254__A
  PIN _254__B
    DIRECTION INPUT ;
    USE SIGNAL ;
    PORT
      LAYER li1 ;
        RECT 2.120 1.445 3.485 1.645 ;
    END
  END _254__B
  PIN _254__Y
    DIRECTION OUTPUT ;
    USE SIGNAL ;
    PORT
      LAYER li1 ;
        RECT 0.535 1.995 0.865 2.465 ;
      LAYER li1 ;
        RECT 0.535 1.815 4.055 1.995 ;
      LAYER li1 ;
        RECT 1.375 1.995 1.705 2.465 ;
      LAYER li1 ;
        RECT 2.215 1.995 2.545 2.465 ;
      LAYER li1 ;
        RECT 2.295 0.975 4.055 1.275 ;
      LAYER li1 ;
        RECT 2.295 0.595 2.465 0.975 ;
      LAYER li1 ;
        RECT 3.055 1.995 3.385 2.465 ;
      LAYER li1 ;
        RECT 3.135 0.595 3.305 0.975 ;
      LAYER li1 ;
        RECT 3.655 1.275 4.055 1.815 ;
    END
  END _254__Y
  PIN load_slew1_A
    DIRECTION INPUT ;
    USE SIGNAL ;
    PORT
      LAYER li1 ;
        RECT 8.030 1.445 9.130 1.645 ;
    END
  END load_slew1_A
  PIN load_slew1_X
    DIRECTION OUTPUT ;
    USE SIGNAL ;
    PORT
      LAYER li1 ;
        RECT 7.245 1.985 7.415 2.465 ;
      LAYER li1 ;
        RECT 4.725 1.815 7.415 1.985 ;
      LAYER li1 ;
        RECT 4.725 1.105 7.415 1.275 ;
      LAYER li1 ;
        RECT 7.245 0.255 7.415 1.105 ;
      LAYER li1 ;
        RECT 6.405 1.985 6.575 2.465 ;
      LAYER li1 ;
        RECT 6.405 0.255 6.575 1.105 ;
      LAYER li1 ;
        RECT 5.565 1.985 5.735 2.465 ;
      LAYER li1 ;
        RECT 5.565 0.255 5.735 1.105 ;
      LAYER li1 ;
        RECT 4.725 1.275 4.980 1.815 ;
      LAYER li1 ;
        RECT 4.725 1.985 4.895 2.465 ;
      LAYER li1 ;
        RECT 4.725 0.255 4.895 1.105 ;
    END
  END load_slew1_X
  OBS
    LAYER li1 ;
      RECT 0.000 2.635 0.090 2.805 ;
      RECT 0.090 1.815 0.365 2.805 ;
      RECT 0.365 2.635 1.035 2.805 ;
      RECT 1.035 2.165 1.205 2.805 ;
      RECT 1.205 2.635 1.875 2.805 ;
      RECT 1.875 2.165 2.045 2.805 ;
      RECT 2.045 2.635 2.715 2.805 ;
      RECT 2.715 2.165 2.885 2.805 ;
      RECT 2.885 2.635 3.555 2.805 ;
      RECT 3.555 2.165 3.840 2.805 ;
      RECT 3.840 2.635 4.140 2.805 ;
      RECT 0.000 -0.085 0.535 0.085 ;
      RECT 0.535 -0.085 0.865 0.885 ;
      RECT 0.865 -0.085 1.375 0.085 ;
      RECT 1.375 -0.085 1.625 0.885 ;
      RECT 1.625 -0.085 4.140 0.085 ;
      RECT 0.090 0.255 0.365 1.265 ;
      RECT 0.365 1.055 1.035 1.265 ;
      RECT 1.035 0.255 1.205 1.265 ;
      RECT 1.205 1.055 1.795 1.265 ;
      RECT 1.795 0.255 2.125 1.265 ;
      RECT 2.125 0.255 2.635 0.425 ;
      RECT 2.635 0.255 2.965 0.785 ;
      RECT 2.965 0.255 3.475 0.425 ;
      RECT 3.475 0.255 3.890 0.805 ;
      RECT 9.095 0.255 9.175 1.275 ;
      RECT 8.925 1.815 9.095 2.465 ;
      RECT 8.925 0.255 9.095 1.275 ;
      RECT 8.845 1.815 8.925 1.985 ;
      RECT 8.845 0.255 8.925 1.275 ;
      RECT 8.335 1.815 8.845 1.985 ;
      RECT 8.335 1.105 8.845 1.275 ;
      RECT 8.255 1.815 8.335 1.985 ;
      RECT 8.255 0.255 8.335 1.275 ;
      RECT 8.085 1.815 8.255 2.460 ;
      RECT 8.085 0.255 8.255 1.275 ;
      RECT 8.005 1.815 8.085 1.985 ;
      RECT 8.005 0.255 8.085 1.275 ;
      RECT 7.850 1.815 8.005 1.985 ;
      RECT 7.850 1.105 8.005 1.275 ;
      RECT 7.675 1.105 7.850 1.985 ;
      RECT 5.225 1.475 7.675 1.645 ;
      RECT 8.755 2.635 9.270 2.805 ;
      RECT 8.425 2.155 8.755 2.805 ;
      RECT 7.915 2.635 8.425 2.805 ;
      RECT 7.585 2.155 7.915 2.805 ;
      RECT 7.075 2.635 7.585 2.805 ;
      RECT 6.745 2.155 7.075 2.805 ;
      RECT 6.235 2.635 6.745 2.805 ;
      RECT 5.905 2.155 6.235 2.805 ;
      RECT 5.395 2.635 5.905 2.805 ;
      RECT 5.065 2.155 5.395 2.805 ;
      RECT 4.555 2.635 5.065 2.805 ;
      RECT 4.225 1.835 4.555 2.805 ;
      RECT 3.750 2.635 4.225 2.805 ;
      RECT 8.675 -0.085 9.270 0.085 ;
      RECT 8.505 -0.085 8.675 0.885 ;
      RECT 7.835 -0.085 8.505 0.085 ;
      RECT 7.665 -0.085 7.835 0.885 ;
      RECT 7.075 -0.085 7.665 0.085 ;
      RECT 6.745 -0.085 7.075 0.885 ;
      RECT 6.235 -0.085 6.745 0.085 ;
      RECT 5.905 -0.085 6.235 0.885 ;
      RECT 5.395 -0.085 5.905 0.085 ;
      RECT 5.065 -0.085 5.395 0.885 ;
      RECT 4.555 -0.085 5.065 0.085 ;
      RECT 4.225 -0.085 4.555 1.235 ;
      RECT 3.750 -0.085 4.225 0.085 ;
  END
END layopt_m5

MACRO layopt_m6
  CLASS BLOCK ;
  FOREIGN layopt_m6 0 0 ;
  ORIGIN 0 0 ;
  SIZE 11.720 BY 2.720 ;
  SYMMETRY X Y ;
  PIN VGND
    DIRECTION INOUT ;
    USE GROUND ;
    SHAPE ABUTMENT ;
    PORT
      LAYER met1 ;
        RECT 0.000 -0.240 9.200 0.240 ;
      LAYER met1 ;
        RECT 8.960 -0.240 11.720 0.240 ;
    END
  END VGND
  PIN VNB
    DIRECTION INOUT ;
    USE GROUND ;
    SHAPE ABUTMENT ;
    PORT
      LAYER pwell ;
        RECT 0.145 -0.085 0.315 0.085 ;
      LAYER pwell ;
        RECT 11.400 -0.085 11.570 0.085 ;
    END
  END VNB
  PIN VPB
    DIRECTION INOUT ;
    USE POWER ;
    SHAPE ABUTMENT ;
    PORT
      LAYER nwell ;
        RECT -0.190 1.305 9.390 2.910 ;
      LAYER nwell ;
        RECT 8.770 1.305 11.910 2.910 ;
    END
  END VPB
  PIN VPWR
    DIRECTION INOUT ;
    USE POWER ;
    SHAPE ABUTMENT ;
    PORT
      LAYER met1 ;
        RECT 0.000 2.480 9.200 2.960 ;
      LAYER met1 ;
        RECT 8.960 2.480 11.720 2.960 ;
    END
  END VPWR
  PIN clkbuf_2_0__f_clk_A
    DIRECTION INPUT ;
    USE SIGNAL ;
    PORT
      LAYER li1 ;
        RECT 0.085 0.765 0.400 1.325 ;
    END
  END clkbuf_2_0__f_clk_A
  PIN clkbuf_2_0__f_clk_X
    DIRECTION OUTPUT ;
    USE SIGNAL ;
    PORT
      LAYER li1 ;
        RECT 2.280 0.280 2.540 0.735 ;
      LAYER li1 ;
        RECT 2.280 0.735 9.025 0.905 ;
      LAYER li1 ;
        RECT 2.280 1.495 9.025 1.720 ;
      LAYER li1 ;
        RECT 2.280 1.720 7.685 1.735 ;
      LAYER li1 ;
        RECT 2.280 1.735 2.540 2.460 ;
      LAYER li1 ;
        RECT 3.140 0.280 3.400 0.735 ;
      LAYER li1 ;
        RECT 3.140 1.735 3.400 2.460 ;
      LAYER li1 ;
        RECT 4.000 0.280 4.260 0.735 ;
      LAYER li1 ;
        RECT 4.000 1.735 4.260 2.460 ;
      LAYER li1 ;
        RECT 4.845 0.280 5.120 0.735 ;
      LAYER li1 ;
        RECT 4.860 1.735 5.120 2.460 ;
      LAYER li1 ;
        RECT 5.705 0.280 5.965 0.735 ;
      LAYER li1 ;
        RECT 5.705 1.735 5.965 2.460 ;
      LAYER li1 ;
        RECT 6.565 0.280 6.825 0.735 ;
      LAYER li1 ;
        RECT 6.565 1.735 6.825 2.460 ;
      LAYER li1 ;
        RECT 7.425 0.280 7.685 0.735 ;
      LAYER li1 ;
        RECT 7.425 1.735 7.685 2.460 ;
      LAYER li1 ;
        RECT 7.860 0.905 9.025 1.495 ;
      LAYER li1 ;
        RECT 8.295 0.280 8.555 0.735 ;
      LAYER li1 ;
        RECT 8.295 1.720 8.585 2.460 ;
    END
  END clkbuf_2_0__f_clk_X
  PIN rebuffer11_A
    DIRECTION INPUT ;
    USE SIGNAL ;
    PORT
      LAYER li1 ;
        RECT 11.250 1.075 11.630 1.315 ;
    END
  END rebuffer11_A
  PIN rebuffer11_X
    DIRECTION OUTPUT ;
    USE SIGNAL ;
    PORT
      LAYER li1 ;
        RECT 10.535 0.255 10.705 0.735 ;
      LAYER li1 ;
        RECT 9.695 0.735 10.705 0.905 ;
      LAYER li1 ;
        RECT 9.695 1.445 10.705 1.615 ;
      LAYER li1 ;
        RECT 10.535 1.615 10.705 2.465 ;
      LAYER li1 ;
        RECT 9.695 0.905 10.190 1.445 ;
      LAYER li1 ;
        RECT 9.695 0.255 9.865 0.735 ;
      LAYER li1 ;
        RECT 9.695 1.615 9.865 2.465 ;
    END
  END rebuffer11_X
  OBS
    LAYER li1 ;
      RECT 0.000 2.635 0.095 2.805 ;
      RECT 0.095 1.825 0.390 2.805 ;
      RECT 0.390 2.635 0.990 2.805 ;
      RECT 0.990 1.825 1.250 2.805 ;
      RECT 1.250 2.635 1.850 2.805 ;
      RECT 1.850 1.835 2.110 2.805 ;
      RECT 2.110 2.630 2.710 2.805 ;
      RECT 2.710 1.905 2.970 2.805 ;
      RECT 2.970 2.630 3.570 2.805 ;
      RECT 3.570 1.905 3.830 2.805 ;
      RECT 3.830 2.630 4.430 2.805 ;
      RECT 4.430 1.905 4.690 2.805 ;
      RECT 4.690 2.630 5.290 2.805 ;
      RECT 5.290 1.905 5.535 2.805 ;
      RECT 5.535 2.630 6.150 2.805 ;
      RECT 6.150 1.905 6.395 2.805 ;
      RECT 6.395 2.630 7.010 2.805 ;
      RECT 7.010 1.905 7.255 2.805 ;
      RECT 7.255 2.630 7.870 2.805 ;
      RECT 7.870 1.905 8.125 2.805 ;
      RECT 8.125 2.635 8.755 2.805 ;
      RECT 8.755 1.890 9.025 2.805 ;
      RECT 9.025 2.635 9.200 2.805 ;
      RECT 0.000 -0.085 0.085 0.085 ;
      RECT 0.085 -0.085 0.390 0.595 ;
      RECT 0.390 -0.085 0.990 0.085 ;
      RECT 0.990 -0.085 1.250 0.610 ;
      RECT 1.250 -0.085 1.850 0.085 ;
      RECT 1.850 -0.085 2.110 0.645 ;
      RECT 2.110 -0.085 2.710 0.085 ;
      RECT 2.710 -0.085 2.970 0.565 ;
      RECT 2.970 -0.085 3.570 0.085 ;
      RECT 3.570 -0.085 3.830 0.565 ;
      RECT 3.830 -0.085 4.430 0.085 ;
      RECT 4.430 -0.085 4.675 0.565 ;
      RECT 4.675 -0.085 5.290 0.085 ;
      RECT 5.290 -0.085 5.535 0.565 ;
      RECT 5.535 -0.085 6.145 0.085 ;
      RECT 6.145 -0.085 6.395 0.565 ;
      RECT 6.395 -0.085 7.005 0.085 ;
      RECT 7.005 -0.085 7.255 0.565 ;
      RECT 7.255 -0.085 7.865 0.085 ;
      RECT 7.865 -0.085 8.125 0.565 ;
      RECT 8.125 -0.085 8.725 0.085 ;
      RECT 8.725 -0.085 9.025 0.565 ;
      RECT 9.025 -0.085 9.200 0.085 ;
      RECT 0.570 0.265 0.815 2.465 ;
      RECT 0.815 0.265 0.820 1.325 ;
      RECT 0.820 1.075 1.430 1.325 ;
      RECT 1.430 0.265 1.680 2.460 ;
      RECT 1.680 1.075 7.690 1.325 ;
      RECT 11.545 1.485 11.625 2.465 ;
      RECT 11.375 0.255 11.545 0.905 ;
      RECT 11.375 1.485 11.545 2.465 ;
      RECT 11.295 0.735 11.375 0.905 ;
      RECT 11.295 1.485 11.375 2.465 ;
      RECT 11.080 0.735 11.295 0.905 ;
      RECT 11.080 1.485 11.295 1.655 ;
      RECT 10.910 0.735 11.080 1.655 ;
      RECT 10.580 1.075 10.910 1.245 ;
      RECT 11.125 2.635 11.720 2.805 ;
      RECT 10.885 1.835 11.125 2.805 ;
      RECT 10.365 2.635 10.885 2.805 ;
      RECT 10.035 1.835 10.365 2.805 ;
      RECT 9.525 2.635 10.035 2.805 ;
      RECT 9.195 1.485 9.525 2.805 ;
      RECT 8.960 2.635 9.195 2.805 ;
      RECT 11.195 -0.085 11.720 0.085 ;
      RECT 10.955 -0.085 11.195 0.565 ;
      RECT 10.365 -0.085 10.955 0.085 ;
      RECT 10.035 -0.085 10.365 0.565 ;
      RECT 9.525 -0.085 10.035 0.085 ;
      RECT 9.195 -0.085 9.525 0.885 ;
      RECT 8.960 -0.085 9.195 0.085 ;
  END
END layopt_m6

MACRO layopt_m7
  CLASS BLOCK ;
  FOREIGN layopt_m7 0 0 ;
  ORIGIN 0 0 ;
  SIZE 5.830 BY 2.720 ;
  SYMMETRY X Y ;
  PIN VGND
    DIRECTION INOUT ;
    USE GROUND ;
    SHAPE ABUTMENT ;
    PORT
      LAYER met1 ;
        RECT 0.000 -0.240 3.220 0.240 ;
      LAYER met1 ;
        RECT 3.070 -0.240 5.830 0.240 ;
    END
  END VGND
  PIN VNB
    DIRECTION INOUT ;
    USE GROUND ;
    SHAPE ABUTMENT ;
    PORT
      LAYER pwell ;
        RECT 2.905 -0.085 3.075 0.085 ;
      LAYER pwell ;
        RECT 5.510 -0.085 5.680 0.085 ;
    END
  END VNB
  PIN VPB
    DIRECTION INOUT ;
    USE POWER ;
    SHAPE ABUTMENT ;
    PORT
      LAYER nwell ;
        RECT -0.190 1.305 3.410 2.910 ;
      LAYER nwell ;
        RECT 2.880 1.305 6.020 2.910 ;
    END
  END VPB
  PIN VPWR
    DIRECTION INOUT ;
    USE POWER ;
    SHAPE ABUTMENT ;
    PORT
      LAYER met1 ;
        RECT 0.000 2.480 3.220 2.960 ;
      LAYER met1 ;
        RECT 3.070 2.480 5.830 2.960 ;
    END
  END VPWR
  PIN _113__A
    DIRECTION INPUT ;
    USE SIGNAL ;
    PORT
      LAYER li1 ;
        RECT 1.595 1.075 2.290 1.275 ;
    END
  END _113__A
  PIN _113__B
    DIRECTION INPUT ;
    USE SIGNAL ;
    PORT
      LAYER li1 ;
        RECT 2.550 0.995 2.795 1.445 ;
      LAYER li1 ;
        RECT 1.255 1.445 2.795 1.615 ;
      LAYER li1 ;
        RECT 0.825 1.075 1.425 1.245 ;
      LAYER li1 ;
        RECT 1.255 1.245 1.425 1.445 ;
    END
  END _113__B
  PIN _113__Y
    DIRECTION OUTPUT ;
    USE SIGNAL ;
    PORT
      LAYER li1 ;
        RECT 0.575 2.125 0.955 2.295 ;
      LAYER li1 ;
        RECT 0.085 1.755 0.745 1.955 ;
      LAYER li1 ;
        RECT 0.575 1.955 0.745 2.125 ;
      LAYER li1 ;
        RECT 0.085 0.345 0.405 0.825 ;
      LAYER li1 ;
        RECT 0.085 0.825 0.255 1.755 ;
    END
  END _113__Y
  PIN rebuffer28_A
    DIRECTION INPUT ;
    USE SIGNAL ;
    PORT
      LAYER li1 ;
        RECT 5.360 1.075 5.740 1.315 ;
    END
  END rebuffer28_A
  PIN rebuffer28_X
    DIRECTION OUTPUT ;
    USE SIGNAL ;
    PORT
      LAYER li1 ;
        RECT 4.645 0.255 4.815 0.735 ;
      LAYER li1 ;
        RECT 3.805 0.735 4.815 0.905 ;
      LAYER li1 ;
        RECT 3.805 1.445 4.815 1.615 ;
      LAYER li1 ;
        RECT 4.645 1.615 4.815 2.465 ;
      LAYER li1 ;
        RECT 3.805 0.905 4.300 1.445 ;
      LAYER li1 ;
        RECT 3.805 0.255 3.975 0.735 ;
      LAYER li1 ;
        RECT 3.805 1.615 3.975 2.465 ;
    END
  END rebuffer28_X
  OBS
    LAYER li1 ;
      RECT 2.965 0.280 3.135 1.955 ;
      RECT 2.670 0.280 2.965 0.825 ;
      RECT 2.670 1.785 2.965 1.955 ;
      RECT 2.665 1.785 2.670 1.955 ;
      RECT 2.335 1.785 2.665 2.465 ;
      RECT 1.085 1.785 2.335 1.955 ;
      RECT 0.915 1.415 1.085 1.955 ;
      RECT 0.595 1.415 0.915 1.585 ;
      RECT 0.425 0.995 0.595 1.585 ;
      RECT 1.495 0.255 1.825 0.905 ;
      RECT 1.085 0.735 1.495 0.905 ;
      RECT 0.915 0.655 1.085 0.905 ;
      RECT 0.805 0.655 0.915 0.825 ;
      RECT 0.575 0.255 0.805 0.825 ;
      RECT 3.135 2.635 3.220 2.805 ;
      RECT 2.835 2.125 3.135 2.805 ;
      RECT 2.165 2.635 2.835 2.805 ;
      RECT 1.535 2.125 2.165 2.805 ;
      RECT 0.405 2.635 1.535 2.805 ;
      RECT 0.105 2.125 0.405 2.805 ;
      RECT 0.000 2.635 0.105 2.805 ;
      RECT 2.165 -0.085 3.220 0.085 ;
      RECT 1.995 -0.085 2.165 0.905 ;
      RECT 1.325 -0.085 1.995 0.085 ;
      RECT 0.975 -0.085 1.325 0.475 ;
      RECT 0.000 -0.085 0.975 0.085 ;
      RECT 5.655 1.485 5.735 2.465 ;
      RECT 5.485 0.255 5.655 0.905 ;
      RECT 5.485 1.485 5.655 2.465 ;
      RECT 5.405 0.735 5.485 0.905 ;
      RECT 5.405 1.485 5.485 2.465 ;
      RECT 5.190 0.735 5.405 0.905 ;
      RECT 5.190 1.485 5.405 1.655 ;
      RECT 5.020 0.735 5.190 1.655 ;
      RECT 4.690 1.075 5.020 1.245 ;
      RECT 5.235 2.635 5.830 2.805 ;
      RECT 4.995 1.835 5.235 2.805 ;
      RECT 4.475 2.635 4.995 2.805 ;
      RECT 4.145 1.835 4.475 2.805 ;
      RECT 3.635 2.635 4.145 2.805 ;
      RECT 3.305 1.485 3.635 2.805 ;
      RECT 3.070 2.635 3.305 2.805 ;
      RECT 5.305 -0.085 5.830 0.085 ;
      RECT 5.065 -0.085 5.305 0.565 ;
      RECT 4.475 -0.085 5.065 0.085 ;
      RECT 4.145 -0.085 4.475 0.565 ;
      RECT 3.635 -0.085 4.145 0.085 ;
      RECT 3.305 -0.085 3.635 0.885 ;
      RECT 3.070 -0.085 3.305 0.085 ;
  END
END layopt_m7

MACRO layopt_m8
  CLASS BLOCK ;
  FOREIGN layopt_m8 0 0 ;
  ORIGIN 0 0 ;
  SIZE 6.750 BY 2.720 ;
  SYMMETRY X Y ;
  PIN VGND
    DIRECTION INOUT ;
    USE GROUND ;
    SHAPE ABUTMENT ;
    PORT
      LAYER met1 ;
        RECT 0.000 -0.240 4.140 0.240 ;
      LAYER met1 ;
        RECT 3.990 -0.240 6.750 0.240 ;
    END
  END VGND
  PIN VNB
    DIRECTION INOUT ;
    USE GROUND ;
    SHAPE ABUTMENT ;
    PORT
      LAYER pwell ;
        RECT 0.150 -0.085 0.320 0.085 ;
      LAYER pwell ;
        RECT 6.430 -0.085 6.600 0.085 ;
    END
  END VNB
  PIN VPB
    DIRECTION INOUT ;
    USE POWER ;
    SHAPE ABUTMENT ;
    PORT
      LAYER nwell ;
        RECT -0.190 1.305 4.330 2.910 ;
      LAYER nwell ;
        RECT 3.800 1.305 6.940 2.910 ;
    END
  END VPB
  PIN VPWR
    DIRECTION INOUT ;
    USE POWER ;
    SHAPE ABUTMENT ;
    PORT
      LAYER met1 ;
        RECT 0.000 2.480 4.140 2.960 ;
      LAYER met1 ;
        RECT 3.990 2.480 6.750 2.960 ;
    END
  END VPWR
  PIN _160__A
    DIRECTION INPUT ;
    USE SIGNAL ;
    PORT
      LAYER li1 ;
        RECT 1.225 1.075 1.700 1.325 ;
    END
  END _160__A
  PIN _160__B
    DIRECTION INPUT ;
    USE SIGNAL ;
    PORT
      LAYER li1 ;
        RECT 0.595 1.075 1.055 1.325 ;
      LAYER li1 ;
        RECT 0.595 1.325 0.830 2.050 ;
    END
  END _160__B
  PIN _160__C
    DIRECTION INPUT ;
    USE SIGNAL ;
    PORT
      LAYER li1 ;
        RECT 0.085 1.075 0.425 1.325 ;
    END
  END _160__C
  PIN _160__X
    DIRECTION OUTPUT ;
    USE SIGNAL ;
    PORT
      LAYER li1 ;
        RECT 2.305 0.265 2.635 0.735 ;
      LAYER li1 ;
        RECT 2.305 0.735 4.055 0.905 ;
      LAYER li1 ;
        RECT 2.345 1.455 4.055 1.625 ;
      LAYER li1 ;
        RECT 2.345 1.625 2.595 2.465 ;
      LAYER li1 ;
        RECT 3.145 0.265 3.475 0.735 ;
      LAYER li1 ;
        RECT 3.185 1.625 3.435 2.465 ;
      LAYER li1 ;
        RECT 3.765 0.905 4.055 1.455 ;
    END
  END _160__X
  PIN rebuffer30_A
    DIRECTION INPUT ;
    USE SIGNAL ;
    PORT
      LAYER li1 ;
        RECT 6.280 1.075 6.660 1.315 ;
    END
  END rebuffer30_A
  PIN rebuffer30_X
    DIRECTION OUTPUT ;
    USE SIGNAL ;
    PORT
      LAYER li1 ;
        RECT 5.565 0.255 5.735 0.735 ;
      LAYER li1 ;
        RECT 4.725 0.735 5.735 0.905 ;
      LAYER li1 ;
        RECT 4.725 1.445 5.735 1.615 ;
      LAYER li1 ;
        RECT 5.565 1.615 5.735 2.465 ;
      LAYER li1 ;
        RECT 4.725 0.905 5.220 1.445 ;
      LAYER li1 ;
        RECT 4.725 0.255 4.895 0.735 ;
      LAYER li1 ;
        RECT 4.725 1.615 4.895 2.465 ;
    END
  END rebuffer30_X
  OBS
    LAYER li1 ;
      RECT 0.085 0.255 0.425 0.905 ;
      RECT 0.085 1.495 0.425 2.465 ;
      RECT 0.425 0.725 0.935 0.905 ;
      RECT 0.425 2.295 0.935 2.465 ;
      RECT 0.935 0.255 1.000 0.905 ;
      RECT 0.935 2.295 1.000 2.465 ;
      RECT 1.000 0.255 1.265 0.905 ;
      RECT 1.000 1.495 1.265 2.465 ;
      RECT 1.265 0.725 1.870 0.905 ;
      RECT 1.265 1.495 1.870 1.665 ;
      RECT 1.870 0.725 2.090 1.665 ;
      RECT 2.090 1.075 3.595 1.245 ;
      RECT 0.000 -0.085 0.595 0.085 ;
      RECT 0.595 -0.085 0.765 0.555 ;
      RECT 0.765 -0.085 1.435 0.085 ;
      RECT 1.435 -0.085 2.135 0.555 ;
      RECT 2.135 -0.085 2.805 0.085 ;
      RECT 2.805 -0.085 2.975 0.555 ;
      RECT 2.975 -0.085 3.645 0.085 ;
      RECT 3.645 -0.085 3.815 0.555 ;
      RECT 3.815 -0.085 4.140 0.085 ;
      RECT 0.000 2.635 1.435 2.805 ;
      RECT 1.435 1.835 2.135 2.805 ;
      RECT 2.135 2.635 2.765 2.805 ;
      RECT 2.765 1.795 3.015 2.805 ;
      RECT 3.015 2.635 3.605 2.805 ;
      RECT 3.605 1.795 3.855 2.805 ;
      RECT 3.855 2.635 4.140 2.805 ;
      RECT 6.575 1.485 6.655 2.465 ;
      RECT 6.405 0.255 6.575 0.905 ;
      RECT 6.405 1.485 6.575 2.465 ;
      RECT 6.325 0.735 6.405 0.905 ;
      RECT 6.325 1.485 6.405 2.465 ;
      RECT 6.110 0.735 6.325 0.905 ;
      RECT 6.110 1.485 6.325 1.655 ;
      RECT 5.940 0.735 6.110 1.655 ;
      RECT 5.610 1.075 5.940 1.245 ;
      RECT 6.155 2.635 6.750 2.805 ;
      RECT 5.915 1.835 6.155 2.805 ;
      RECT 5.395 2.635 5.915 2.805 ;
      RECT 5.065 1.835 5.395 2.805 ;
      RECT 4.555 2.635 5.065 2.805 ;
      RECT 4.225 1.485 4.555 2.805 ;
      RECT 3.990 2.635 4.225 2.805 ;
      RECT 6.225 -0.085 6.750 0.085 ;
      RECT 5.985 -0.085 6.225 0.565 ;
      RECT 5.395 -0.085 5.985 0.085 ;
      RECT 5.065 -0.085 5.395 0.565 ;
      RECT 4.555 -0.085 5.065 0.085 ;
      RECT 4.225 -0.085 4.555 0.885 ;
      RECT 3.990 -0.085 4.225 0.085 ;
  END
END layopt_m8

MACRO layopt_m9
  CLASS BLOCK ;
  FOREIGN layopt_m9 0 0 ;
  ORIGIN 0 0 ;
  SIZE 4.450 BY 2.720 ;
  SYMMETRY X Y ;
  PIN VGND
    DIRECTION INOUT ;
    USE GROUND ;
    SHAPE ABUTMENT ;
    PORT
      LAYER met1 ;
        RECT 0.000 -0.240 1.840 0.240 ;
      LAYER met1 ;
        RECT 1.690 -0.240 4.450 0.240 ;
    END
  END VGND
  PIN VNB
    DIRECTION INOUT ;
    USE GROUND ;
    SHAPE ABUTMENT ;
    PORT
      LAYER pwell ;
        RECT 1.525 -0.085 1.695 0.085 ;
      LAYER pwell ;
        RECT 4.130 -0.085 4.300 0.085 ;
    END
  END VNB
  PIN VPB
    DIRECTION INOUT ;
    USE POWER ;
    SHAPE ABUTMENT ;
    PORT
      LAYER nwell ;
        RECT -0.190 1.305 2.030 2.910 ;
      LAYER nwell ;
        RECT 1.500 1.305 4.640 2.910 ;
    END
  END VPB
  PIN VPWR
    DIRECTION INOUT ;
    USE POWER ;
    SHAPE ABUTMENT ;
    PORT
      LAYER met1 ;
        RECT 0.000 2.480 1.840 2.960 ;
      LAYER met1 ;
        RECT 1.690 2.480 4.450 2.960 ;
    END
  END VPWR
  PIN _155__A1
    DIRECTION INPUT ;
    USE SIGNAL ;
    PORT
      LAYER li1 ;
        RECT 1.425 0.955 1.755 1.615 ;
    END
  END _155__A1
  PIN _155__A2
    DIRECTION INPUT ;
    USE SIGNAL ;
    PORT
      LAYER li1 ;
        RECT 0.835 1.100 1.235 1.340 ;
      LAYER li1 ;
        RECT 1.065 1.340 1.235 1.645 ;
    END
  END _155__A2
  PIN _155__B1
    DIRECTION INPUT ;
    USE SIGNAL ;
    PORT
      LAYER li1 ;
        RECT 0.110 1.355 0.325 1.685 ;
    END
  END _155__B1
  PIN _155__Y
    DIRECTION OUTPUT ;
    USE SIGNAL ;
    PORT
      LAYER li1 ;
        RECT 0.495 1.510 0.875 1.680 ;
      LAYER li1 ;
        RECT 0.540 1.680 0.875 2.465 ;
      LAYER li1 ;
        RECT 0.100 0.955 0.665 1.125 ;
      LAYER li1 ;
        RECT 0.495 1.125 0.665 1.510 ;
      LAYER li1 ;
        RECT 0.100 0.280 0.385 0.955 ;
    END
  END _155__Y
  PIN rebuffer32_A
    DIRECTION INPUT ;
    USE SIGNAL ;
    PORT
      LAYER li1 ;
        RECT 3.980 1.075 4.360 1.315 ;
    END
  END rebuffer32_A
  PIN rebuffer32_X
    DIRECTION OUTPUT ;
    USE SIGNAL ;
    PORT
      LAYER li1 ;
        RECT 3.265 0.255 3.435 0.735 ;
      LAYER li1 ;
        RECT 2.425 0.735 3.435 0.905 ;
      LAYER li1 ;
        RECT 2.425 1.445 3.435 1.615 ;
      LAYER li1 ;
        RECT 3.265 1.615 3.435 2.465 ;
      LAYER li1 ;
        RECT 2.425 0.905 2.920 1.445 ;
      LAYER li1 ;
        RECT 2.425 0.255 2.595 0.735 ;
      LAYER li1 ;
        RECT 2.425 1.615 2.595 2.465 ;
    END
  END rebuffer32_X
  OBS
    LAYER li1 ;
      RECT 1.460 0.280 1.720 0.785 ;
      RECT 0.790 0.615 1.460 0.785 ;
      RECT 0.555 0.280 0.790 0.785 ;
      RECT 1.290 -0.085 1.840 0.085 ;
      RECT 0.960 -0.085 1.290 0.445 ;
      RECT 0.000 -0.085 0.960 0.085 ;
      RECT 1.695 2.635 1.840 2.805 ;
      RECT 1.365 1.825 1.695 2.805 ;
      RECT 0.370 2.635 1.365 2.805 ;
      RECT 0.115 1.855 0.370 2.805 ;
      RECT 0.000 2.635 0.115 2.805 ;
      RECT 4.275 1.485 4.355 2.465 ;
      RECT 4.105 0.255 4.275 0.905 ;
      RECT 4.105 1.485 4.275 2.465 ;
      RECT 4.025 0.735 4.105 0.905 ;
      RECT 4.025 1.485 4.105 2.465 ;
      RECT 3.810 0.735 4.025 0.905 ;
      RECT 3.810 1.485 4.025 1.655 ;
      RECT 3.640 0.735 3.810 1.655 ;
      RECT 3.310 1.075 3.640 1.245 ;
      RECT 3.855 2.635 4.450 2.805 ;
      RECT 3.615 1.835 3.855 2.805 ;
      RECT 3.095 2.635 3.615 2.805 ;
      RECT 2.765 1.835 3.095 2.805 ;
      RECT 2.255 2.635 2.765 2.805 ;
      RECT 1.925 1.485 2.255 2.805 ;
      RECT 1.690 2.635 1.925 2.805 ;
      RECT 3.925 -0.085 4.450 0.085 ;
      RECT 3.685 -0.085 3.925 0.565 ;
      RECT 3.095 -0.085 3.685 0.085 ;
      RECT 2.765 -0.085 3.095 0.565 ;
      RECT 2.255 -0.085 2.765 0.085 ;
      RECT 1.925 -0.085 2.255 0.885 ;
      RECT 1.690 -0.085 1.925 0.085 ;
  END
END layopt_m9

MACRO layopt_m10
  CLASS BLOCK ;
  FOREIGN layopt_m10 0 0 ;
  ORIGIN 0 0 ;
  SIZE 8.085 BY 2.720 ;
  SYMMETRY X Y ;
  PIN VGND
    DIRECTION INOUT ;
    USE GROUND ;
    SHAPE ABUTMENT ;
    PORT
      LAYER met1 ;
        RECT 0.000 -0.240 4.140 0.240 ;
      LAYER met1 ;
        RECT 3.945 -0.240 8.085 0.240 ;
    END
  END VGND
  PIN VNB
    DIRECTION INOUT ;
    USE GROUND ;
    SHAPE ABUTMENT ;
    PORT
      LAYER pwell ;
        RECT 0.145 -0.085 0.315 0.085 ;
      LAYER pwell ;
        RECT 4.095 -0.085 4.265 0.085 ;
    END
  END VNB
  PIN VPB
    DIRECTION INOUT ;
    USE POWER ;
    SHAPE ABUTMENT ;
    PORT
      LAYER nwell ;
        RECT -0.190 1.305 4.330 2.910 ;
      LAYER nwell ;
        RECT 3.755 1.305 8.275 2.910 ;
    END
  END VPB
  PIN VPWR
    DIRECTION INOUT ;
    USE POWER ;
    SHAPE ABUTMENT ;
    PORT
      LAYER met1 ;
        RECT 0.000 2.480 4.140 2.960 ;
      LAYER met1 ;
        RECT 3.945 2.480 8.085 2.960 ;
    END
  END VPWR
  PIN _247__A
    DIRECTION INPUT ;
    USE SIGNAL ;
    PORT
      LAYER li1 ;
        RECT 0.680 1.075 3.535 1.325 ;
    END
  END _247__A
  PIN _247__Y
    DIRECTION OUTPUT ;
    USE SIGNAL ;
    PORT
      LAYER li1 ;
        RECT 0.085 0.715 4.055 0.905 ;
      LAYER li1 ;
        RECT 0.085 0.905 0.430 1.495 ;
      LAYER li1 ;
        RECT 0.085 1.495 4.055 1.665 ;
      LAYER li1 ;
        RECT 0.680 0.255 1.010 0.715 ;
      LAYER li1 ;
        RECT 0.680 1.665 1.010 2.465 ;
      LAYER li1 ;
        RECT 1.520 0.255 1.850 0.715 ;
      LAYER li1 ;
        RECT 1.520 1.665 1.850 2.465 ;
      LAYER li1 ;
        RECT 2.360 0.255 2.690 0.715 ;
      LAYER li1 ;
        RECT 2.360 1.665 2.690 2.465 ;
      LAYER li1 ;
        RECT 3.200 0.255 3.530 0.715 ;
      LAYER li1 ;
        RECT 3.200 1.665 3.530 2.465 ;
      LAYER li1 ;
        RECT 3.735 0.905 4.055 1.495 ;
    END
  END _247__Y
  PIN rebuffer5_A
    DIRECTION INPUT ;
    USE SIGNAL ;
    PORT
      LAYER li1 ;
        RECT 4.225 1.075 5.130 1.315 ;
    END
  END rebuffer5_A
  PIN rebuffer5_X
    DIRECTION OUTPUT ;
    USE SIGNAL ;
    PORT
      LAYER li1 ;
        RECT 5.640 0.255 5.810 0.735 ;
      LAYER li1 ;
        RECT 5.640 0.735 7.490 0.905 ;
      LAYER li1 ;
        RECT 5.640 1.445 7.490 1.615 ;
      LAYER li1 ;
        RECT 5.640 1.615 5.810 2.465 ;
      LAYER li1 ;
        RECT 6.155 0.905 7.490 1.445 ;
      LAYER li1 ;
        RECT 6.480 0.255 6.650 0.735 ;
      LAYER li1 ;
        RECT 6.480 1.615 6.650 2.465 ;
      LAYER li1 ;
        RECT 7.320 0.255 7.490 0.735 ;
      LAYER li1 ;
        RECT 7.320 1.615 7.490 2.465 ;
    END
  END rebuffer5_X
  OBS
    LAYER li1 ;
      RECT 0.000 -0.085 0.255 0.085 ;
      RECT 0.255 -0.085 0.510 0.545 ;
      RECT 0.510 -0.085 1.180 0.085 ;
      RECT 1.180 -0.085 1.350 0.545 ;
      RECT 1.350 -0.085 2.020 0.085 ;
      RECT 2.020 -0.085 2.190 0.545 ;
      RECT 2.190 -0.085 2.860 0.085 ;
      RECT 2.860 -0.085 3.030 0.545 ;
      RECT 3.030 -0.085 3.700 0.085 ;
      RECT 3.700 -0.085 4.005 0.545 ;
      RECT 4.005 -0.085 4.140 0.085 ;
      RECT 0.000 2.635 0.255 2.805 ;
      RECT 0.255 1.835 0.510 2.805 ;
      RECT 0.510 2.635 1.180 2.805 ;
      RECT 1.180 1.835 1.350 2.805 ;
      RECT 1.350 2.635 2.020 2.805 ;
      RECT 2.020 1.835 2.190 2.805 ;
      RECT 2.190 2.635 2.860 2.805 ;
      RECT 2.860 1.835 3.030 2.805 ;
      RECT 3.030 2.635 3.700 2.805 ;
      RECT 3.700 1.835 4.000 2.805 ;
      RECT 4.000 2.635 4.140 2.805 ;
      RECT 4.720 0.255 5.050 0.905 ;
      RECT 4.720 1.485 5.050 2.465 ;
      RECT 5.050 0.735 5.300 0.905 ;
      RECT 5.050 1.485 5.300 1.655 ;
      RECT 5.300 0.735 5.470 1.655 ;
      RECT 5.470 1.075 5.770 1.245 ;
      RECT 3.945 -0.085 4.380 0.085 ;
      RECT 4.380 -0.085 4.550 0.565 ;
      RECT 4.550 -0.085 5.220 0.085 ;
      RECT 5.220 -0.085 5.390 0.565 ;
      RECT 5.390 -0.085 5.980 0.085 ;
      RECT 5.980 -0.085 6.310 0.565 ;
      RECT 6.310 -0.085 6.820 0.085 ;
      RECT 6.820 -0.085 7.150 0.565 ;
      RECT 7.150 -0.085 7.660 0.085 ;
      RECT 7.660 -0.085 7.990 0.885 ;
      RECT 7.990 -0.085 8.085 0.085 ;
      RECT 3.945 2.635 4.380 2.805 ;
      RECT 4.380 1.485 4.550 2.805 ;
      RECT 4.550 2.635 5.220 2.805 ;
      RECT 5.220 1.835 5.460 2.805 ;
      RECT 5.460 2.635 5.980 2.805 ;
      RECT 5.980 1.835 6.310 2.805 ;
      RECT 6.310 2.635 6.820 2.805 ;
      RECT 6.820 1.835 7.150 2.805 ;
      RECT 7.150 2.635 7.660 2.805 ;
      RECT 7.660 1.485 7.990 2.805 ;
      RECT 7.990 2.635 8.085 2.805 ;
  END
END layopt_m10

MACRO layopt_m11
  CLASS BLOCK ;
  FOREIGN layopt_m11 0 0 ;
  ORIGIN 0 0 ;
  SIZE 4.865 BY 2.720 ;
  SYMMETRY X Y ;
  PIN VGND
    DIRECTION INOUT ;
    USE GROUND ;
    SHAPE ABUTMENT ;
    PORT
      LAYER met1 ;
        RECT 0.000 -0.240 2.300 0.240 ;
      LAYER met1 ;
        RECT 2.105 -0.240 4.865 0.240 ;
    END
  END VGND
  PIN VNB
    DIRECTION INOUT ;
    USE GROUND ;
    SHAPE ABUTMENT ;
    PORT
      LAYER pwell ;
        RECT 0.150 -0.085 0.320 0.085 ;
      LAYER pwell ;
        RECT 4.545 -0.085 4.715 0.085 ;
    END
  END VNB
  PIN VPB
    DIRECTION INOUT ;
    USE POWER ;
    SHAPE ABUTMENT ;
    PORT
      LAYER nwell ;
        RECT -0.190 1.305 2.490 2.910 ;
      LAYER nwell ;
        RECT 1.915 1.305 5.055 2.910 ;
    END
  END VPB
  PIN VPWR
    DIRECTION INOUT ;
    USE POWER ;
    SHAPE ABUTMENT ;
    PORT
      LAYER met1 ;
        RECT 0.000 2.480 2.300 2.960 ;
      LAYER met1 ;
        RECT 2.105 2.480 4.865 2.960 ;
    END
  END VPWR
  PIN _115__A_N
    DIRECTION INPUT ;
    USE SIGNAL ;
    PORT
      LAYER li1 ;
        RECT 0.090 1.075 0.440 1.315 ;
    END
  END _115__A_N
  PIN _115__B
    DIRECTION INPUT ;
    USE SIGNAL ;
    PORT
      LAYER li1 ;
        RECT 0.610 1.075 1.085 1.315 ;
    END
  END _115__B
  PIN _115__Y
    DIRECTION OUTPUT ;
    USE SIGNAL ;
    PORT
      LAYER li1 ;
        RECT 1.000 1.835 2.170 2.005 ;
      LAYER li1 ;
        RECT 1.000 2.005 1.330 2.465 ;
      LAYER li1 ;
        RECT 1.420 0.255 2.170 0.545 ;
      LAYER li1 ;
        RECT 1.800 0.545 2.170 1.835 ;
    END
  END _115__Y
  PIN rebuffer52_A
    DIRECTION INPUT ;
    USE SIGNAL ;
    PORT
      LAYER li1 ;
        RECT 4.395 1.075 4.775 1.315 ;
    END
  END rebuffer52_A
  PIN rebuffer52_X
    DIRECTION OUTPUT ;
    USE SIGNAL ;
    PORT
      LAYER li1 ;
        RECT 3.680 0.255 3.850 0.735 ;
      LAYER li1 ;
        RECT 2.840 0.735 3.850 0.905 ;
      LAYER li1 ;
        RECT 2.840 1.445 3.850 1.615 ;
      LAYER li1 ;
        RECT 3.680 1.615 3.850 2.465 ;
      LAYER li1 ;
        RECT 2.840 0.905 3.335 1.445 ;
      LAYER li1 ;
        RECT 2.840 0.255 3.010 0.735 ;
      LAYER li1 ;
        RECT 2.840 1.615 3.010 2.465 ;
    END
  END rebuffer52_X
  OBS
    LAYER li1 ;
      RECT 0.000 -0.085 0.580 0.085 ;
      RECT 0.580 -0.085 0.910 0.545 ;
      RECT 0.910 -0.085 2.300 0.085 ;
      RECT 0.000 2.635 0.580 2.805 ;
      RECT 0.580 1.835 0.830 2.805 ;
      RECT 0.830 2.635 1.500 2.805 ;
      RECT 1.500 2.175 1.715 2.805 ;
      RECT 1.715 2.635 2.300 2.805 ;
      RECT 0.090 0.525 0.360 0.905 ;
      RECT 0.090 1.495 0.360 1.825 ;
      RECT 0.360 0.735 0.370 0.905 ;
      RECT 0.360 1.495 0.370 1.825 ;
      RECT 0.370 0.735 1.255 0.905 ;
      RECT 0.370 1.495 1.255 1.665 ;
      RECT 1.255 0.735 1.425 1.665 ;
      RECT 1.425 1.075 1.630 1.325 ;
      RECT 4.690 1.485 4.770 2.465 ;
      RECT 4.520 0.255 4.690 0.905 ;
      RECT 4.520 1.485 4.690 2.465 ;
      RECT 4.440 0.735 4.520 0.905 ;
      RECT 4.440 1.485 4.520 2.465 ;
      RECT 4.225 0.735 4.440 0.905 ;
      RECT 4.225 1.485 4.440 1.655 ;
      RECT 4.055 0.735 4.225 1.655 ;
      RECT 3.725 1.075 4.055 1.245 ;
      RECT 4.270 2.635 4.865 2.805 ;
      RECT 4.030 1.835 4.270 2.805 ;
      RECT 3.510 2.635 4.030 2.805 ;
      RECT 3.180 1.835 3.510 2.805 ;
      RECT 2.670 2.635 3.180 2.805 ;
      RECT 2.340 1.485 2.670 2.805 ;
      RECT 2.105 2.635 2.340 2.805 ;
      RECT 4.340 -0.085 4.865 0.085 ;
      RECT 4.100 -0.085 4.340 0.565 ;
      RECT 3.510 -0.085 4.100 0.085 ;
      RECT 3.180 -0.085 3.510 0.565 ;
      RECT 2.670 -0.085 3.180 0.085 ;
      RECT 2.340 -0.085 2.670 0.885 ;
      RECT 2.105 -0.085 2.340 0.085 ;
  END
END layopt_m11

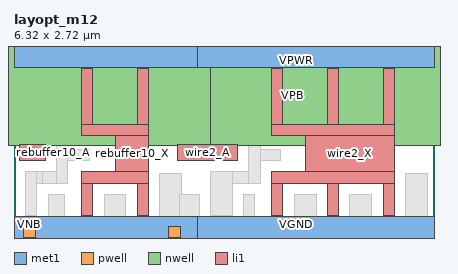
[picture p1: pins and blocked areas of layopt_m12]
MACRO layopt_m12
  CLASS BLOCK ;
  FOREIGN layopt_m12 0 0 ;
  ORIGIN 0 0 ;
  SIZE 6.320 BY 2.720 ;
  SYMMETRY X Y ;
  PIN VGND
    DIRECTION INOUT ;
    USE GROUND ;
    SHAPE ABUTMENT ;
    PORT
      LAYER met1 ;
        RECT 0.000 -0.240 2.760 0.240 ;
      LAYER met1 ;
        RECT 2.180 -0.240 6.320 0.240 ;
    END
  END VGND
  PIN VNB
    DIRECTION INOUT ;
    USE GROUND ;
    SHAPE ABUTMENT ;
    PORT
      LAYER pwell ;
        RECT 0.150 -0.085 0.320 0.085 ;
      LAYER pwell ;
        RECT 2.330 -0.085 2.500 0.085 ;
    END
  END VNB
  PIN VPB
    DIRECTION INOUT ;
    USE POWER ;
    SHAPE ABUTMENT ;
    PORT
      LAYER nwell ;
        RECT -0.190 1.305 2.950 2.910 ;
      LAYER nwell ;
        RECT 1.990 1.305 6.510 2.910 ;
    END
  END VPB
  PIN VPWR
    DIRECTION INOUT ;
    USE POWER ;
    SHAPE ABUTMENT ;
    PORT
      LAYER met1 ;
        RECT 0.000 2.480 2.760 2.960 ;
      LAYER met1 ;
        RECT 2.180 2.480 6.320 2.960 ;
    END
  END VPWR
  PIN rebuffer10_A
    DIRECTION INPUT ;
    USE SIGNAL ;
    PORT
      LAYER li1 ;
        RECT 0.090 1.075 0.470 1.315 ;
    END
  END rebuffer10_A
  PIN rebuffer10_X
    DIRECTION OUTPUT ;
    USE SIGNAL ;
    PORT
      LAYER li1 ;
        RECT 1.015 0.255 1.185 0.735 ;
      LAYER li1 ;
        RECT 1.015 0.735 2.025 0.905 ;
      LAYER li1 ;
        RECT 1.015 1.445 2.025 1.615 ;
      LAYER li1 ;
        RECT 1.015 1.615 1.185 2.465 ;
      LAYER li1 ;
        RECT 1.530 0.905 2.025 1.445 ;
      LAYER li1 ;
        RECT 1.855 0.255 2.025 0.735 ;
      LAYER li1 ;
        RECT 1.855 1.615 2.025 2.465 ;
    END
  END rebuffer10_X
  PIN wire2_A
    DIRECTION INPUT ;
    USE SIGNAL ;
    PORT
      LAYER li1 ;
        RECT 2.460 1.075 3.365 1.315 ;
    END
  END wire2_A
  PIN wire2_X
    DIRECTION OUTPUT ;
    USE SIGNAL ;
    PORT
      LAYER li1 ;
        RECT 3.875 0.255 4.045 0.735 ;
      LAYER li1 ;
        RECT 3.875 0.735 5.725 0.905 ;
      LAYER li1 ;
        RECT 3.875 1.445 5.725 1.615 ;
      LAYER li1 ;
        RECT 3.875 1.615 4.045 2.465 ;
      LAYER li1 ;
        RECT 4.390 0.905 5.725 1.445 ;
      LAYER li1 ;
        RECT 4.715 0.255 4.885 0.735 ;
      LAYER li1 ;
        RECT 4.715 1.615 4.885 2.465 ;
      LAYER li1 ;
        RECT 5.555 0.255 5.725 0.735 ;
      LAYER li1 ;
        RECT 5.555 1.615 5.725 2.465 ;
    END
  END wire2_X
  OBS
    LAYER li1 ;
      RECT 0.095 1.485 0.175 2.465 ;
      RECT 0.175 0.255 0.345 0.905 ;
      RECT 0.175 1.485 0.345 2.465 ;
      RECT 0.345 0.735 0.425 0.905 ;
      RECT 0.345 1.485 0.425 2.465 ;
      RECT 0.425 0.735 0.640 0.905 ;
      RECT 0.425 1.485 0.640 1.655 ;
      RECT 0.640 0.735 0.810 1.655 ;
      RECT 0.810 1.075 1.140 1.245 ;
      RECT 0.000 2.635 0.595 2.805 ;
      RECT 0.595 1.835 0.835 2.805 ;
      RECT 0.835 2.635 1.355 2.805 ;
      RECT 1.355 1.835 1.685 2.805 ;
      RECT 1.685 2.635 2.195 2.805 ;
      RECT 2.195 1.485 2.525 2.805 ;
      RECT 2.525 2.635 2.760 2.805 ;
      RECT 0.000 -0.085 0.525 0.085 ;
      RECT 0.525 -0.085 0.765 0.565 ;
      RECT 0.765 -0.085 1.355 0.085 ;
      RECT 1.355 -0.085 1.685 0.565 ;
      RECT 1.685 -0.085 2.195 0.085 ;
      RECT 2.195 -0.085 2.525 0.885 ;
      RECT 2.525 -0.085 2.760 0.085 ;
      RECT 2.955 0.255 3.285 0.905 ;
      RECT 2.955 1.485 3.285 2.465 ;
      RECT 3.285 0.735 3.535 0.905 ;
      RECT 3.285 1.485 3.535 1.655 ;
      RECT 3.535 0.735 3.705 1.655 ;
      RECT 3.705 1.075 4.005 1.245 ;
      RECT 2.180 -0.085 2.615 0.085 ;
      RECT 2.615 -0.085 2.785 0.565 ;
      RECT 2.785 -0.085 3.455 0.085 ;
      RECT 3.455 -0.085 3.625 0.565 ;
      RECT 3.625 -0.085 4.215 0.085 ;
      RECT 4.215 -0.085 4.545 0.565 ;
      RECT 4.545 -0.085 5.055 0.085 ;
      RECT 5.055 -0.085 5.385 0.565 ;
      RECT 5.385 -0.085 5.895 0.085 ;
      RECT 5.895 -0.085 6.225 0.885 ;
      RECT 6.225 -0.085 6.320 0.085 ;
      RECT 2.180 2.635 2.615 2.805 ;
      RECT 2.615 1.485 2.785 2.805 ;
      RECT 2.785 2.635 3.455 2.805 ;
      RECT 3.455 1.835 3.695 2.805 ;
      RECT 3.695 2.635 4.215 2.805 ;
      RECT 4.215 1.835 4.545 2.805 ;
      RECT 4.545 2.635 5.055 2.805 ;
      RECT 5.055 1.835 5.385 2.805 ;
      RECT 5.385 2.635 5.895 2.805 ;
      RECT 5.895 1.485 6.225 2.805 ;
      RECT 6.225 2.635 6.320 2.805 ;
      RECT 2.485 -0.085 2.785 0.565 ;
      RECT 2.485 1.485 2.785 2.805 ;
  END
END layopt_m12

END LIBRARY
